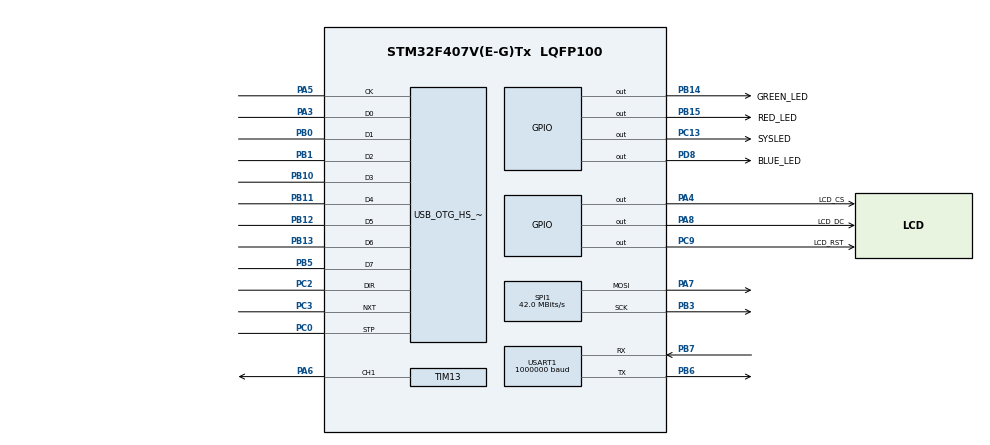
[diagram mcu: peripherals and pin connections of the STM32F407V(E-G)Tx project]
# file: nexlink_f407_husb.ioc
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Dma.Request0=SPI1_TX
Dma.SPI1_TX.0.Direction=DMA_MEMORY_TO_PERIPH
Dma.SPI1_TX.0.FIFOMode=DMA_FIFOMODE_DISABLE
Dma.SPI1_TX.0.Instance=DMA2_Stream3
Dma.SPI1_TX.0.MemDataAlignment=DMA_MDATAALIGN_BYTE
Dma.SPI1_TX.0.MemInc=DMA_MINC_ENABLE
Dma.SPI1_TX.0.Mode=DMA_NORMAL
Dma.SPI1_TX.0.PeriphDataAlignment=DMA_PDATAALIGN_BYTE
Dma.SPI1_TX.0.PeriphInc=DMA_PINC_DISABLE
Dma.SPI1_TX.0.Priority=DMA_PRIORITY_LOW
Mcu.Family=STM32F4
Mcu.Name=STM32F407V(E-G)Tx
Mcu.Package=LQFP100
NVIC.DMA2_Stream3_IRQn=true\:0\:0\:false\:false\:true\:false\:true\:true
NVIC.OTG_HS_IRQn=true\:0\:0\:false\:false\:true\:false\:true\:true
NVIC.PriorityGroup=NVIC_PRIORITYGROUP_4
PA13.Mode=Serial_Wire
PA13.Signal=SYS_JTMS-SWDIO
PA14.Mode=Serial_Wire
PA14.Signal=SYS_JTCK-SWCLK
PA3.Mode=Device_HS
PA3.Signal=USB_OTG_HS_ULPI_D0
PA4.GPIO_Label=LCD_CS
PA4.GPIO_ModeDefaultOutputPP=GPIO_MODE_OUTPUT_PP
PA4.GPIO_PuPd=GPIO_PULLUP
PA4.GPIO_Speed=GPIO_SPEED_FREQ_VERY_HIGH
PA4.PinState=GPIO_PIN_SET
PA4.Signal=GPIO_Output
PA5.Mode=Device_HS
PA5.Signal=USB_OTG_HS_ULPI_CK
PA6.Signal=S_TIM13_CH1
PA7.Mode=TX_Only_Simplex_Unidirect_Master
PA7.Signal=SPI1_MOSI
PA8.GPIO_Label=LCD_DC
PA8.GPIO_ModeDefaultOutputPP=GPIO_MODE_OUTPUT_PP
PA8.GPIO_PuPd=GPIO_PULLUP
PA8.GPIO_Speed=GPIO_SPEED_FREQ_VERY_HIGH
PA8.PinState=GPIO_PIN_SET
PA8.Signal=GPIO_Output
PB0.Mode=Device_HS
PB0.Signal=USB_OTG_HS_ULPI_D1
PB1.Mode=Device_HS
PB1.Signal=USB_OTG_HS_ULPI_D2
PB10.Mode=Device_HS
PB10.Signal=USB_OTG_HS_ULPI_D3
PB11.Mode=Device_HS
PB11.Signal=USB_OTG_HS_ULPI_D4
PB12.Mode=Device_HS
PB12.Signal=USB_OTG_HS_ULPI_D5
PB13.Mode=Device_HS
PB13.Signal=USB_OTG_HS_ULPI_D6
PB14.GPIO_Label=GREEN_LED
PB14.GPIO_ModeDefaultOutputPP=GPIO_MODE_OUTPUT_PP
PB14.GPIO_PuPd=GPIO_PULLUP
PB14.GPIO_Speed=GPIO_SPEED_FREQ_LOW
PB14.PinState=GPIO_PIN_RESET
PB14.Signal=GPIO_Output
PB15.GPIO_Label=RED_LED
PB15.GPIO_ModeDefaultOutputPP=GPIO_MODE_OUTPUT_PP
PB15.GPIO_PuPd=GPIO_PULLUP
PB15.GPIO_Speed=GPIO_SPEED_FREQ_LOW
PB15.PinState=GPIO_PIN_RESET
PB15.Signal=GPIO_Output
PB3.Mode=TX_Only_Simplex_Unidirect_Master
PB3.Signal=SPI1_SCK
PB5.Mode=Device_HS
PB5.Signal=USB_OTG_HS_ULPI_D7
PB6.Mode=Asynchronous
PB6.Signal=USART1_TX
PB7.Mode=Asynchronous
PB7.Signal=USART1_RX
PB9.Signal=CAN1_TX
PC0.Mode=Device_HS
PC0.Signal=USB_OTG_HS_ULPI_STP
PC13-ANTI_TAMP.GPIO_Label=SYSLED
PC13-ANTI_TAMP.GPIO_ModeDefaultOutputPP=GPIO_MODE_OUTPUT_PP
PC13-ANTI_TAMP.GPIO_PuPd=GPIO_PULLUP
PC13-ANTI_TAMP.GPIO_Speed=GPIO_SPEED_FREQ_LOW
PC13-ANTI_TAMP.PinState=GPIO_PIN_RESET
PC13-ANTI_TAMP.Signal=GPIO_Output
PC14-OSC32_IN.Mode=LSE-External-Oscillator
PC14-OSC32_IN.Signal=RCC_OSC32_IN
PC15-OSC32_OUT.Mode=LSE-External-Oscillator
PC15-OSC32_OUT.Signal=RCC_OSC32_OUT
PC2.Mode=Device_HS
PC2.Signal=USB_OTG_HS_ULPI_DIR
PC3.Mode=Device_HS
PC3.Signal=USB_OTG_HS_ULPI_NXT
PC9.GPIO_Label=LCD_RST
PC9.GPIO_PuPd=GPIO_PULLUP
PC9.GPIO_Speed=GPIO_SPEED_FREQ_VERY_HIGH
PC9.PinState=GPIO_PIN_SET
PC9.Signal=GPIO_Output
PD8.GPIO_Label=BLUE_LED
PD8.GPIO_ModeDefaultOutputPP=GPIO_MODE_OUTPUT_PP
PD8.GPIO_PuPd=GPIO_PULLUP
PD8.GPIO_Speed=GPIO_SPEED_FREQ_LOW
PD8.PinState=GPIO_PIN_RESET
PD8.Signal=GPIO_Output
PH0-OSC_IN.Mode=HSE-External-Oscillator
PH0-OSC_IN.Signal=RCC_OSC_IN
PH1-OSC_OUT.Mode=HSE-External-Oscillator
PH1-OSC_OUT.Signal=RCC_OSC_OUT
ProjectManager.HeapSize=0x800
ProjectManager.StackSize=0x1000
ProjectManager.TargetToolchain=MDK-ARM V5.32
RCC.48MHZClocksFreq_Value=48000000
RCC.AHBFreq_Value=168000000
RCC.APB1CLKDivider=RCC_HCLK_DIV4
RCC.APB1Freq_Value=42000000
RCC.APB1TimFreq_Value=84000000
RCC.APB2CLKDivider=RCC_HCLK_DIV2
RCC.APB2Freq_Value=84000000
RCC.APB2TimFreq_Value=168000000
RCC.CortexFreq_Value=168000000
RCC.HCLKFreq_Value=168000000
RCC.HSE_VALUE=8000000
RCC.HSI_VALUE=16000000
RCC.PLLM=4
RCC.PLLN=168
RCC.PLLQ=7
RCC.PLLSourceVirtual=RCC_PLLSOURCE_HSE
RCC.SYSCLKFreq_VALUE=168000000
RCC.SYSCLKSource=RCC_SYSCLKSOURCE_PLLCLK
RCC.VCOOutputFreq_Value=336000000
SH.S_TIM13_CH1.0=TIM13_CH1,PWM Generation1 CH1
SPI1.CalculateBaudRate=42.0 MBits/s
SPI1.Direction=SPI_DIRECTION_2LINES
SPI1.Mode=SPI_MODE_MASTER
SPI1.VirtualType=VM_MASTER
TIM13.Channel=TIM_CHANNEL_1
TIM13.OCPolarity_1=TIM_OCPOLARITY_LOW
TIM13.Period=1000-1
TIM13.Prescaler=84-1
TIM13.Pulse=0
USART1.BaudRate=1000000
USART1.VirtualMode=VM_ASYNC
USB_DEVICE.CLASS_NAME_HS=CDC
USB_DEVICE.VirtualMode-CDC_HS=Cdc
USB_DEVICE.VirtualModeHS=Cdc_HS
USB_OTG_HS.VirtualMode-Device_HS=Device_HS
VP_TIM13_VS_ClockSourceINT.Mode=Enable_Timer
VP_USB_DEVICE_VS_USB_DEVICE_CDC_HS.Mode=CDC_HS
board=custom

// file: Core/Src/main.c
/* USER CODE BEGIN Header */
/**
  ******************************************************************************
  * @file           : main.c
  * @brief          : Main program body
  ******************************************************************************
  * @attention
  *
  * Copyright (c) 2024 STMicroelectronics.
  * All rights reserved.
  *
  * This software is licensed under terms that can be found in the LICENSE file
  * in the root directory of this software component.
  * If no LICENSE file comes with this software, it is provided AS-IS.
  *
  ******************************************************************************
  */
/* USER CODE END Header */
#include "main.h"
#include "dma.h"
#include "spi.h"
#include "tim.h"
#include "usart.h"
#include "gpio.h"

/* USER CODE BEGIN Includes */
#include <stdarg.h>
#include "usbd_def.h"
#include "usbd_desc.h"
#include "usbd_core.h"
#include "usbd_nex_link.h"
#include "nex_usb.h"
#include "stdio.h"
#include "queue.h"
#include "lcd.h"
#include "lv_anim_light.h"
/* USER CODE END Includes */

/* USER CODE BEGIN PV */
USBD_HandleTypeDef hUSB;

/* USER CODE END PV */

void SystemClock_Config(void);

/* USER CODE BEGIN 0 */
int fputc(int ch, FILE* f)
{
  HAL_UART_Transmit(&huart1, (uint8_t*)&ch, 1, HAL_MAX_DELAY);
  return ch;
}

uint16_t grambuff[1024];
//uint8_t grambufftemp[1024];
nex_usb_des des;

//uint8_t refrash_screen(void)
//{
//  uint16_t line = 0;

////  dbmsg("wait:%d", HAL_GetTick());
//  do
//  {
//    line = LCD_ReadScanLine();
//  }
//  while(line < 200);   // 轮询
//  LCD_Color_Fill(0, 0, 240, 240, grambuff);
////  dbmsg("start:%d", HAL_GetTick());
//  return 0;
//}

lv_anim_t a;
void set_brightness_value(void *obj, int32_t value)
{
	dbmsg("brightness: %d", value);
	Set_PWM_DutyCycle(value%1000);
}

/* USER CODE END 0 */

int main(void)
{
  /* USER CODE BEGIN 1 */
//	long index = 0;
//	long i,j,p;
  /* USER CODE END 1 */

  /* MCU Configuration--------------------------------------------------------*/

  /* Reset of all peripherals, Initializes the Flash interface and the Systick. */
  HAL_Init();

  /* Configure the system clock */
  SystemClock_Config();

  /* Initialize all configured peripherals */
  MX_GPIO_Init();
  MX_USART1_UART_Init();
  MX_DMA_Init();
  MX_SPI1_Init();
  MX_TIM13_Init();
  /* USER CODE BEGIN 2 */
  dbmsg("hello");

  USBD_Init(&hUSB, &FS_Desc, DEVICE_HS);
  USBD_RegisterClass(&hUSB, &USBD_NEX_LINK);
  USBD_NEX_LINK_Init(&hUSB, grambuff, &des);
  USBD_Start(&hUSB);

  HAL_TIM_PWM_Start(&htim13, TIM_CHANNEL_1);
  LCD_Init();
	a = lv_anim_start(999,0,set_brightness_value,1000);
//	LCD_Address_Set(0,0,LCD_W-1,LCD_H-1);
//	for(i = 0; i < (LCD_H * LCD_W * 2) / 960; i ++)
//	{
//		for (j = 0; j < 2; j++)
//		{
//				for (p = 0; p < 480; p++)
//				{
//						grambufftemp[p + j * 480] =( ((((index++) % (960 * 2))/ 960) == 1) ? 0xFF : 0);
//				}
//		}
//    LCD_DMA_Transfer16Bit(grambufftemp, 960, DMA_MEMINC_ENABLE);
//	}

  dbmsg("ok");

  /* USER CODE END 2 */

  /* Infinite loop */
  while(1)
  {

    /* USER CODE BEGIN 3 */
    HAL_GPIO_WritePin(GREEN_LED_GPIO_Port, GREEN_LED_Pin, GPIO_PIN_SET);
    HAL_GPIO_WritePin(BLUE_LED_GPIO_Port, BLUE_LED_Pin, GPIO_PIN_SET);
    HAL_GPIO_WritePin(RED_LED_GPIO_Port, RED_LED_Pin, GPIO_PIN_SET);
		lv_anim_run(&a);
    HAL_Delay(5);

  }
  /* USER CODE END 3 */
}

void SystemClock_Config(void)
{
  RCC_OscInitTypeDef RCC_OscInitStruct = {0};
  RCC_ClkInitTypeDef RCC_ClkInitStruct = {0};

  /** Configure the main internal regulator output voltage
  */
  __HAL_RCC_PWR_CLK_ENABLE();
  __HAL_PWR_VOLTAGESCALING_CONFIG(PWR_REGULATOR_VOLTAGE_SCALE1);

  /** Initializes the RCC Oscillators according to the specified parameters
  * in the RCC_OscInitTypeDef structure.
  */
  RCC_OscInitStruct.OscillatorType = RCC_OSCILLATORTYPE_HSE;
  RCC_OscInitStruct.HSEState = RCC_HSE_ON;
  RCC_OscInitStruct.PLL.PLLState = RCC_PLL_ON;
  RCC_OscInitStruct.PLL.PLLSource = RCC_PLLSOURCE_HSE;
  RCC_OscInitStruct.PLL.PLLM = 4;
  RCC_OscInitStruct.PLL.PLLN = 168;
  RCC_OscInitStruct.PLL.PLLP = RCC_PLLP_DIV2;
  RCC_OscInitStruct.PLL.PLLQ = 7;
  if(HAL_RCC_OscConfig(&RCC_OscInitStruct) != HAL_OK)
  {
    Error_Handler();
  }

  /** Initializes the CPU, AHB and APB buses clocks
  */
  RCC_ClkInitStruct.ClockType = RCC_CLOCKTYPE_HCLK | RCC_CLOCKTYPE_SYSCLK
                                | RCC_CLOCKTYPE_PCLK1 | RCC_CLOCKTYPE_PCLK2;
  RCC_ClkInitStruct.SYSCLKSource = RCC_SYSCLKSOURCE_PLLCLK;
  RCC_ClkInitStruct.AHBCLKDivider = RCC_SYSCLK_DIV1;
  RCC_ClkInitStruct.APB1CLKDivider = RCC_HCLK_DIV4;
  RCC_ClkInitStruct.APB2CLKDivider = RCC_HCLK_DIV1;

  if(HAL_RCC_ClockConfig(&RCC_ClkInitStruct, FLASH_LATENCY_5) != HAL_OK)
  {
    Error_Handler();
  }
}

void Error_Handler(void)
{
  __disable_irq();
  while(1)
  {
  }
}
